VERSION 5.8 ;
BUSBITCHARS "[]" ;
DIVIDERCHAR "/" ;
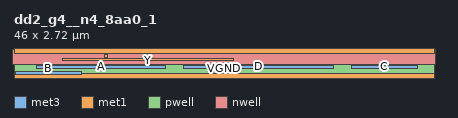
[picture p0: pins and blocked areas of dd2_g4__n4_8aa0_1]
MACRO dd2_g4__n4_8aa0_1
  CLASS CORE ;
  ORIGIN 0 0 ;
  SIZE 46.000 BY 2.720 ;
  SYMMETRY X Y ;
  SITE unithd ;
  PIN A
    DIRECTION INPUT ;
    USE SIGNAL ;
    ANTENNAGATEAREA 0.213000 ;
    PORT
      LAYER met3 ;
        RECT 2.485 0.855 16.615 1.185 ;
    END
  END A
  PIN B
    DIRECTION INPUT ;
    USE SIGNAL ;
    ANTENNAGATEAREA 0.213000 ;
    PORT
      LAYER met3 ;
        RECT 0.185 0.175 7.415 0.505 ;
    END
  END B
  PIN C
    DIRECTION INPUT ;
    USE SIGNAL ;
    ANTENNAGATEAREA 0.426000 ;
    PORT
      LAYER met3 ;
        RECT 36.985 0.855 44.215 1.185 ;
    END
  END C
  PIN D
    DIRECTION INPUT ;
    USE SIGNAL ;
    ANTENNAGATEAREA 0.426000 ;
    PORT
      LAYER met3 ;
        RECT 18.585 0.855 35.015 1.185 ;
    END
  END D
  PIN VGND
    DIRECTION INOUT ;
    USE GROUND ;
    SHAPE ABUTMENT ;
    PORT
      LAYER met1 ;
        RECT 0.000 -0.240 46.000 0.240 ;
    END
  END VGND
  PIN VNB
    DIRECTION INOUT ;
    USE GROUND ;
    PORT
      LAYER pwell ;
        RECT 0.000 0.000 46.000 1.305 ;
    END
  END VNB
  PIN VPB
    DIRECTION INOUT ;
    USE POWER ;
    PORT
      LAYER nwell ;
        RECT -0.190 1.305 46.190 2.910 ;
    END
  END VPB
  PIN VPWR
    DIRECTION INOUT ;
    USE POWER ;
    SHAPE ABUTMENT ;
    PORT
      LAYER met1 ;
        RECT 0.000 2.480 46.000 2.960 ;
    END
  END VPWR
  PIN Y
    DIRECTION OUTPUT ;
    USE SIGNAL ;
    ANTENNADIFFAREA 0.768400 ;
    PORT
      LAYER met1 ;
        RECT 5.365 1.670 5.685 1.730 ;
        RECT 9.965 1.670 10.285 1.730 ;
        RECT 21.465 1.670 21.785 1.730 ;
        RECT 23.765 1.670 24.085 1.730 ;
        RECT 5.360 1.730 24.090 1.870 ;
        RECT 5.365 1.870 5.685 1.930 ;
        RECT 21.465 1.870 21.785 1.930 ;
        RECT 23.765 1.870 24.085 1.930 ;
        RECT 9.965 1.870 10.285 2.010 ;
        RECT 9.960 2.010 10.290 2.340 ;
    END
  END Y
  OBS
    LAYER li1 ;
      RECT 0.000 -0.085 46.000 0.085 ;
      RECT 0.000 2.635 46.000 2.805 ;
      RECT 33.690 0.085 33.860 0.255 ;
      RECT 45.190 0.085 45.360 0.255 ;
      RECT 31.310 0.255 31.640 0.635 ;
      RECT 33.610 0.255 33.940 0.635 ;
      RECT 45.110 0.255 45.440 0.635 ;
      RECT 23.910 0.255 24.240 0.380 ;
      RECT 23.760 0.380 24.240 0.710 ;
      RECT 24.410 0.255 24.740 0.380 ;
      RECT 24.410 0.380 24.780 0.710 ;
      RECT 30.810 0.255 31.140 0.380 ;
      RECT 30.660 0.380 31.140 0.710 ;
      RECT 33.110 0.255 33.440 0.380 ;
      RECT 32.960 0.380 33.440 0.710 ;
      RECT 42.310 0.255 42.640 0.380 ;
      RECT 42.160 0.380 42.640 0.710 ;
      RECT 42.810 0.255 43.140 0.380 ;
      RECT 42.810 0.380 43.180 0.710 ;
      RECT 44.610 0.255 44.940 0.380 ;
      RECT 44.460 0.380 44.940 0.710 ;
      RECT 23.165 0.380 23.515 0.710 ;
      RECT 23.165 0.710 23.335 1.075 ;
      RECT 23.165 1.075 24.340 1.315 ;
      RECT 25.465 0.380 25.815 0.710 ;
      RECT 25.465 0.710 25.635 1.075 ;
      RECT 25.465 1.075 26.640 1.315 ;
      RECT 27.765 0.380 28.115 0.710 ;
      RECT 27.765 0.710 27.935 1.075 ;
      RECT 27.765 1.075 28.940 1.315 ;
      RECT 30.065 0.380 30.415 0.710 ;
      RECT 30.065 0.710 30.235 1.075 ;
      RECT 30.065 1.075 31.240 1.315 ;
      RECT 32.365 0.380 32.715 0.710 ;
      RECT 32.365 0.710 32.535 1.075 ;
      RECT 32.365 1.075 33.540 1.315 ;
      RECT 34.665 0.380 35.015 0.710 ;
      RECT 34.665 0.710 34.835 1.075 ;
      RECT 34.665 1.075 35.840 1.315 ;
      RECT 36.965 0.380 37.315 0.710 ;
      RECT 36.965 0.710 37.135 1.075 ;
      RECT 36.965 1.075 38.140 1.315 ;
      RECT 39.265 0.380 39.615 0.710 ;
      RECT 39.265 0.710 39.435 1.075 ;
      RECT 39.265 1.075 40.440 1.315 ;
      RECT 41.565 0.380 41.915 0.710 ;
      RECT 41.565 0.710 41.735 1.075 ;
      RECT 41.565 1.075 42.740 1.315 ;
      RECT 43.865 0.380 44.215 0.710 ;
      RECT 43.865 0.710 44.035 1.075 ;
      RECT 43.865 1.075 45.040 1.315 ;
      RECT 26.210 1.505 26.540 2.010 ;
      RECT 26.060 2.010 26.540 2.340 ;
      RECT 26.210 2.340 26.540 2.465 ;
      RECT 26.710 1.505 27.040 2.010 ;
      RECT 26.710 2.010 27.080 2.340 ;
      RECT 26.710 2.340 27.040 2.465 ;
      RECT 28.510 1.505 28.840 2.010 ;
      RECT 28.360 2.010 28.840 2.340 ;
      RECT 28.510 2.340 28.840 2.465 ;
      RECT 35.410 1.505 35.740 2.010 ;
      RECT 35.260 2.010 35.740 2.340 ;
      RECT 35.410 2.340 35.740 2.465 ;
      RECT 37.710 1.505 38.040 2.010 ;
      RECT 37.560 2.010 38.040 2.340 ;
      RECT 37.710 2.340 38.040 2.465 ;
      RECT 40.010 1.505 40.340 2.010 ;
      RECT 39.860 2.010 40.340 2.340 ;
      RECT 40.010 2.340 40.340 2.465 ;
      RECT 40.510 1.505 40.840 2.010 ;
      RECT 40.510 2.010 40.880 2.340 ;
      RECT 40.510 2.340 40.840 2.465 ;
      RECT 29.010 1.505 29.340 2.465 ;
      RECT 35.910 1.505 36.240 2.465 ;
      RECT 38.210 1.505 38.540 2.465 ;
      RECT 29.090 2.465 29.260 2.635 ;
      RECT 35.990 2.465 36.160 2.635 ;
      RECT 38.290 2.465 38.460 2.635 ;
      RECT 31.390 0.085 31.560 0.255 ;
      RECT 6.010 0.255 6.340 0.635 ;
      RECT 17.510 0.255 17.840 0.635 ;
      RECT 19.810 0.255 20.140 0.635 ;
      RECT 19.890 0.085 20.060 0.255 ;
      RECT 1.490 0.085 1.660 0.255 ;
      RECT 6.090 0.085 6.260 0.255 ;
      RECT 0.910 0.255 1.240 0.380 ;
      RECT 0.760 0.380 1.240 0.710 ;
      RECT 5.510 0.255 5.840 0.380 ;
      RECT 5.360 0.380 5.840 0.710 ;
      RECT 17.010 0.255 17.340 0.380 ;
      RECT 16.860 0.380 17.340 0.710 ;
      RECT 0.165 0.380 0.515 0.710 ;
      RECT 0.165 0.710 0.335 1.075 ;
      RECT 0.165 1.075 1.340 1.315 ;
      RECT 2.465 0.380 2.815 0.710 ;
      RECT 2.465 0.710 2.635 1.075 ;
      RECT 2.465 1.075 3.640 1.315 ;
      RECT 4.765 0.380 5.115 0.710 ;
      RECT 4.765 0.710 4.935 1.075 ;
      RECT 4.765 1.075 5.940 1.315 ;
      RECT 7.065 0.380 7.415 0.710 ;
      RECT 3.210 1.505 3.540 2.010 ;
      RECT 3.060 2.010 3.540 2.340 ;
      RECT 3.210 2.340 3.540 2.465 ;
      RECT 7.810 1.505 8.140 2.010 ;
      RECT 7.660 2.010 8.140 2.340 ;
      RECT 7.810 2.340 8.140 2.465 ;
      RECT 10.110 1.505 10.440 2.010 ;
      RECT 9.960 2.010 10.440 2.340 ;
      RECT 10.110 2.340 10.440 2.465 ;
      RECT 10.610 1.505 10.940 2.010 ;
      RECT 10.610 2.010 10.980 2.340 ;
      RECT 10.610 2.340 10.940 2.465 ;
      RECT 12.410 1.505 12.740 2.010 ;
      RECT 12.260 2.010 12.740 2.340 ;
      RECT 12.410 2.340 12.740 2.465 ;
      RECT 14.710 1.505 15.040 2.010 ;
      RECT 14.560 2.010 15.040 2.340 ;
      RECT 14.710 2.340 15.040 2.465 ;
      RECT 15.210 1.505 15.540 2.010 ;
      RECT 15.210 2.010 15.580 2.340 ;
      RECT 15.210 2.340 15.540 2.465 ;
      RECT 7.065 0.710 7.235 1.075 ;
      RECT 7.065 1.075 8.240 1.315 ;
      RECT 9.365 0.380 9.715 0.710 ;
      RECT 9.365 0.710 9.535 1.075 ;
      RECT 9.365 1.075 10.540 1.315 ;
      RECT 11.665 0.380 12.015 0.710 ;
      RECT 11.665 0.710 11.835 1.075 ;
      RECT 11.665 1.075 12.840 1.315 ;
      RECT 13.965 0.380 14.315 0.710 ;
      RECT 13.965 0.710 14.135 1.075 ;
      RECT 13.965 1.075 15.140 1.315 ;
      RECT 16.265 0.380 16.615 0.710 ;
      RECT 16.265 0.710 16.435 1.075 ;
      RECT 16.265 1.075 17.440 1.315 ;
      RECT 18.565 0.380 18.915 0.710 ;
      RECT 18.565 0.710 18.735 1.075 ;
      RECT 18.565 1.075 19.740 1.315 ;
      RECT 20.865 0.380 21.215 0.710 ;
      RECT 20.865 0.710 21.035 1.075 ;
      RECT 20.865 1.075 22.040 1.315 ;
      RECT 19.310 0.255 19.640 0.380 ;
      RECT 3.710 1.505 4.040 2.465 ;
      RECT 8.310 1.505 8.640 2.465 ;
      RECT 12.910 1.505 13.240 2.465 ;
      RECT 19.160 0.380 19.640 0.710 ;
      RECT 21.610 0.255 21.940 0.380 ;
      RECT 21.460 0.380 21.940 0.710 ;
      RECT 3.790 2.465 3.960 2.635 ;
      RECT 8.390 2.465 8.560 2.635 ;
      RECT 12.990 2.465 13.160 2.635 ;
      RECT 22.110 0.255 22.440 0.380 ;
      RECT 22.110 0.380 22.480 0.710 ;
      RECT 17.590 0.085 17.760 0.255 ;
      RECT 1.410 0.255 1.740 0.635 ;
    LAYER met1 ;
      RECT 0.185 0.380 0.515 0.710 ;
      RECT 2.485 0.380 2.815 0.710 ;
      RECT 4.785 0.380 5.115 0.710 ;
      RECT 5.360 0.380 5.690 0.710 ;
      RECT 7.085 0.380 7.415 0.710 ;
      RECT 9.385 0.380 9.715 0.710 ;
      RECT 11.685 0.380 12.015 0.710 ;
      RECT 16.285 0.380 16.615 0.710 ;
      RECT 16.860 0.380 17.190 0.710 ;
      RECT 18.585 0.380 18.915 0.710 ;
      RECT 19.160 0.380 19.490 0.710 ;
      RECT 21.460 0.380 21.790 0.710 ;
      RECT 23.185 0.380 23.515 0.710 ;
      RECT 23.760 0.380 24.090 0.710 ;
      RECT 24.450 0.380 24.780 0.710 ;
      RECT 25.485 0.380 25.815 0.710 ;
      RECT 27.785 0.380 28.115 0.710 ;
      RECT 30.085 0.380 30.415 0.710 ;
      RECT 30.660 0.380 30.990 0.710 ;
      RECT 32.385 0.380 32.715 0.710 ;
      RECT 32.960 0.380 33.290 0.710 ;
      RECT 34.685 0.380 35.015 0.710 ;
      RECT 36.985 0.380 37.315 0.710 ;
      RECT 39.285 0.380 39.615 0.710 ;
      RECT 41.585 0.380 41.915 0.710 ;
      RECT 42.850 0.380 43.180 0.710 ;
      RECT 43.885 0.380 44.215 0.710 ;
      RECT 44.460 0.380 44.790 0.710 ;
      RECT 0.760 0.380 1.090 0.710 ;
      RECT 13.985 0.380 14.315 0.710 ;
      RECT 20.885 0.380 21.215 0.710 ;
      RECT 0.765 0.710 1.085 0.850 ;
      RECT 7.665 0.790 7.985 0.850 ;
      RECT 13.990 0.710 14.310 0.850 ;
      RECT 20.890 0.710 21.210 0.850 ;
      RECT 0.760 0.850 21.215 0.990 ;
      RECT 0.765 0.990 1.085 1.050 ;
      RECT 7.665 0.990 7.985 1.050 ;
      RECT 13.990 0.990 14.310 1.050 ;
      RECT 20.890 0.990 21.210 1.050 ;
      RECT 22.150 0.380 22.480 0.710 ;
      RECT 42.160 0.380 42.490 0.710 ;
      RECT 22.155 0.710 22.475 0.850 ;
      RECT 42.165 0.710 42.485 0.850 ;
      RECT 22.150 0.850 42.490 0.990 ;
      RECT 22.155 0.990 22.475 1.050 ;
      RECT 42.165 0.990 42.485 1.050 ;
      RECT 3.065 1.230 3.385 1.290 ;
      RECT 4.790 1.230 5.110 1.290 ;
      RECT 9.390 1.230 9.710 1.290 ;
      RECT 16.865 1.230 17.185 1.290 ;
      RECT 3.060 1.290 17.190 1.430 ;
      RECT 3.065 1.430 3.385 1.490 ;
      RECT 4.790 1.430 5.110 1.490 ;
      RECT 9.390 1.430 9.710 1.490 ;
      RECT 16.865 1.430 17.185 1.490 ;
      RECT 23.190 1.230 23.510 1.290 ;
      RECT 27.790 1.230 28.110 1.290 ;
      RECT 37.565 1.230 37.885 1.290 ;
      RECT 44.465 1.230 44.785 1.290 ;
      RECT 23.185 1.290 44.790 1.430 ;
      RECT 23.190 1.430 23.510 1.490 ;
      RECT 27.790 1.430 28.110 1.490 ;
      RECT 37.565 1.430 37.885 1.490 ;
      RECT 44.465 1.430 44.785 1.490 ;
      RECT 24.455 1.670 24.775 1.730 ;
      RECT 30.665 1.670 30.985 1.730 ;
      RECT 24.450 1.730 30.990 1.870 ;
      RECT 24.455 1.870 24.775 1.930 ;
      RECT 30.665 1.870 30.985 1.930 ;
      RECT 32.965 1.670 33.285 1.730 ;
      RECT 42.855 1.670 43.175 1.730 ;
      RECT 32.960 1.730 43.180 1.870 ;
      RECT 32.965 1.870 33.285 1.930 ;
      RECT 42.855 1.870 43.175 1.930 ;
      RECT 3.060 2.010 3.390 2.340 ;
      RECT 7.660 2.010 7.990 2.340 ;
      RECT 10.650 2.010 10.980 2.340 ;
      RECT 12.260 2.010 12.590 2.340 ;
      RECT 14.560 2.010 14.890 2.340 ;
      RECT 15.250 2.010 15.580 2.340 ;
      RECT 26.060 2.010 26.390 2.340 ;
      RECT 26.750 2.010 27.080 2.340 ;
      RECT 28.360 2.010 28.690 2.340 ;
      RECT 35.260 2.010 35.590 2.340 ;
      RECT 37.560 2.010 37.890 2.340 ;
      RECT 39.860 2.010 40.190 2.340 ;
      RECT 40.550 2.010 40.880 2.340 ;
    LAYER met2 ;
      RECT 0.210 0.155 0.490 0.210 ;
      RECT 0.190 0.210 0.510 0.675 ;
      RECT 7.110 0.155 7.390 0.210 ;
      RECT 7.090 0.210 7.410 0.675 ;
      RECT 0.765 0.415 1.085 1.050 ;
      RECT 13.990 0.415 14.310 1.050 ;
      RECT 20.890 0.415 21.210 1.050 ;
      RECT 22.155 0.415 22.475 1.050 ;
      RECT 42.165 0.415 42.485 1.050 ;
      RECT 2.490 0.415 2.810 1.150 ;
      RECT 2.510 1.150 2.790 1.205 ;
      RECT 16.290 0.415 16.610 1.150 ;
      RECT 16.310 1.150 16.590 1.205 ;
      RECT 18.590 0.415 18.910 1.150 ;
      RECT 18.610 1.150 18.890 1.205 ;
      RECT 25.490 0.415 25.810 1.150 ;
      RECT 25.510 1.150 25.790 1.205 ;
      RECT 32.390 0.415 32.710 1.150 ;
      RECT 32.410 1.150 32.690 1.205 ;
      RECT 34.690 0.415 35.010 1.150 ;
      RECT 34.710 1.150 34.990 1.205 ;
      RECT 36.990 0.415 37.310 1.150 ;
      RECT 37.010 1.150 37.290 1.205 ;
      RECT 39.290 0.415 39.610 1.150 ;
      RECT 39.310 1.150 39.590 1.205 ;
      RECT 41.590 0.415 41.910 1.150 ;
      RECT 41.610 1.150 41.890 1.205 ;
      RECT 43.890 0.415 44.210 1.150 ;
      RECT 43.910 1.150 44.190 1.205 ;
      RECT 4.790 0.415 5.110 1.490 ;
      RECT 9.390 0.415 9.710 1.490 ;
      RECT 16.865 0.415 17.185 1.490 ;
      RECT 23.190 0.415 23.510 1.490 ;
      RECT 27.790 0.415 28.110 1.490 ;
      RECT 44.465 0.415 44.785 1.490 ;
      RECT 11.690 0.415 12.010 1.830 ;
      RECT 11.710 1.830 11.990 1.885 ;
      RECT 19.165 0.415 19.485 1.830 ;
      RECT 19.185 1.830 19.465 1.885 ;
      RECT 30.090 0.415 30.410 1.830 ;
      RECT 30.110 1.830 30.390 1.885 ;
      RECT 5.365 0.415 5.685 1.930 ;
      RECT 21.465 0.415 21.785 1.930 ;
      RECT 23.765 0.415 24.085 1.930 ;
      RECT 24.455 0.415 24.775 1.930 ;
      RECT 30.665 0.415 30.985 1.930 ;
      RECT 32.965 0.415 33.285 1.930 ;
      RECT 42.855 0.415 43.175 1.930 ;
      RECT 3.065 1.230 3.385 2.305 ;
      RECT 7.665 0.790 7.985 2.305 ;
      RECT 9.965 1.670 10.285 2.305 ;
      RECT 10.675 0.155 10.955 0.210 ;
      RECT 10.655 0.210 10.975 2.305 ;
      RECT 14.585 0.155 14.865 0.210 ;
      RECT 14.565 0.210 14.885 2.305 ;
      RECT 26.085 0.155 26.365 0.210 ;
      RECT 26.065 0.210 26.385 2.305 ;
      RECT 35.285 1.515 35.565 1.570 ;
      RECT 35.265 1.570 35.585 2.305 ;
      RECT 37.565 1.230 37.885 2.305 ;
      RECT 39.885 0.155 40.165 0.210 ;
      RECT 39.865 0.210 40.185 2.305 ;
      RECT 12.265 2.045 12.585 2.510 ;
      RECT 12.285 2.510 12.565 2.565 ;
      RECT 15.255 2.045 15.575 2.510 ;
      RECT 15.275 2.510 15.555 2.565 ;
      RECT 26.755 2.045 27.075 2.510 ;
      RECT 26.775 2.510 27.055 2.565 ;
      RECT 28.365 2.045 28.685 2.510 ;
      RECT 28.385 2.510 28.665 2.565 ;
      RECT 40.555 2.045 40.875 2.510 ;
      RECT 40.575 2.510 40.855 2.565 ;
    LAYER met3 ;
      RECT 10.650 0.175 40.190 0.505 ;
      RECT 11.685 1.535 35.590 1.865 ;
      RECT 12.260 2.215 40.880 2.545 ;
  END
END dd2_g4__n4_8aa0_1
END LIBRARY
